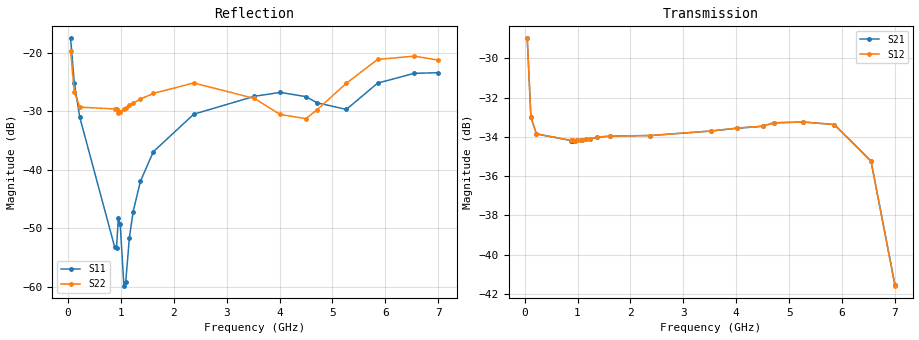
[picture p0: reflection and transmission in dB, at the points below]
! Integrated Device Technology
! Corporate Headquarters
! 6024 Silver Creek Valley Road
! San Jose, CA 95138  USA
! Phone:  1-408-284-8200
! Toll Free:  1-800-223-1366
! Webpage:  http://www.idt.com/
! Timing and RF Division
! 515 Groton Road, Suite 102
! Westford, MA 01886-6024
! Device:  F2258
! Description: Voltage Variable RF Attenuator
! Frequency:  50.0 -  6000.00 MHz
! Package:  3x3 mm Thin QFN Plastic Package: 16 pin
! Ports:  2 RF, 2 DC
!  Pin  1  = NC
!  Pin  2  = NC
!  Pin  3  = RF2  = Port 2
!  Pin  4  = GND
!  Pin  5  = Vdd
!  Pin  6  = NC
!  Pin  7  = VCTRL
!  Pin  8  = NC
!  Pin  9  = GND
!  Pin 10  = RF1  = Port 1
!  Pin 11  = NC
!  Pin 12  = NC
!  Pin 13  = NC
!  Pin 14  = NC
!  Pin 15  = NC
!  Pin 16  = NC
! Vcntrl:  1.860 Volts
! Vdd:  +3.300 Volts
! Current:  1.156 mA
! Data:  The device was measured on a the F2258 evaluation board which has
!  individual transmission lines to the RF pins.  Data was collected
!  using a calibrated network analyzer.  The evaluation board was
!  de-embedded using a TRL calibration technique.
!  The reference plane is the edge of the package pin.
! Misc:  SN 10
!  Action Tracker AT0285
! Date Measured:  2014-12-10
! Date:  2016-01-13  MJV
! Note:
!  Integrated Device Technology supplies this data as a sample of measured
!  data at the package pin for this product.  Your particular data for this
!  product may vary.
!  Data was taken at 25 degrees C.
!  Integrated Device Technology reserves the right to change this data at anytime.
!Freq_(GHz)  S11M_(dB)  S11P_(deg)  S21M_(dB)  S21P_(deg)  S12M_(dB)  S12P_(deg)  S22M_(dB)  S22P_(deg)
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# GHz S dB R 50
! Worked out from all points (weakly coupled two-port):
!   201 points, 50 MHz to 7 GHz, reference 50 ohm
!   highest |S21| = -28.98 dB at 50 MHz (marker M1); lowest = -41.5 dB at 7 GHz (marker M2)
!   lowest |S11| = -59.8 dB at 1.058 GHz (marker M3), VSWR 1.00, Z = 49.9 + j0.0488 ohm
!   |S11| at or under -10 dB: start of sweep to end of sweep
!   |S22| runs from -31.3 to -19.7 dB; largest |S21 - S12| = 5.9e-05
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0.05  -17.55 -110.7  -28.98 -63.4  -28.98 -63.3  -19.66 -100.3
0.1195  -25.11 -106.5  -33.00 -33.6  -33.00 -33.6  -26.65 -64.7
0.22375  -31.04 -109.9  -33.85 -19.6  -33.84 -19.6  -29.30 -36.6
0.884  -53.23 166.5  -34.19 -9.1  -34.18 -9.1  -29.62 -2.9
0.91875  -53.37 148.4  -34.19 -9.1  -34.18 -9.1  -29.70 -2.6
0.9535  -48.17 -160.4  -34.20 -9.0  -34.19 -9.0  -30.39 1.4
0.98825  -49.34 -171.9  -34.18 -9.0  -34.17 -9.0  -30.22 0.3
1.05775  -59.82 151.4  -34.16 -9.0  -34.16 -9.0  -29.66 0.8
1.0925  -59.16 109.9  -34.14 -9.0  -34.14 -9.0  -29.47 0.9
1.162  -51.59 63.9  -34.12 -9.0  -34.12 -9.1  -29.02 1.0
1.2315  -47.19 42.3  -34.10 -9.2  -34.09 -9.2  -28.60 1.0
1.3705  -41.96 35.0  -34.02 -9.8  -34.01 -9.8  -27.94 1.5
1.61375  -36.93 31.6  -33.96 -11.3  -33.96 -11.3  -26.96 0.9
2.37825  -30.51 47.5  -33.93 -15.5  -33.93 -15.5  -25.17 3.1
3.525  -27.45 91.3  -33.70 -22.8  -33.70 -22.8  -27.82 18.6
4.0115  -26.79 104.4  -33.56 -26.7  -33.55 -26.6  -30.56 22.5
4.498  -27.50 103.5  -33.46 -30.4  -33.45 -30.4  -31.27 13.6
4.7065  -28.55 95.5  -33.28 -32.5  -33.29 -32.5  -29.78 3.7
5.2625  -29.70 53.9  -33.24 -38.7  -33.24 -38.7  -25.22 -17.3
5.85325  -25.20 29.5  -33.37 -48.7  -33.37 -48.7  -21.15 -25.4
6.54825  -23.52 44.9  -35.23 -67.6  -35.25 -67.6  -20.59 -55.3
7  -23.42 84.3  -41.54 -64.4  -41.58 -64.1  -21.27 -124.8
